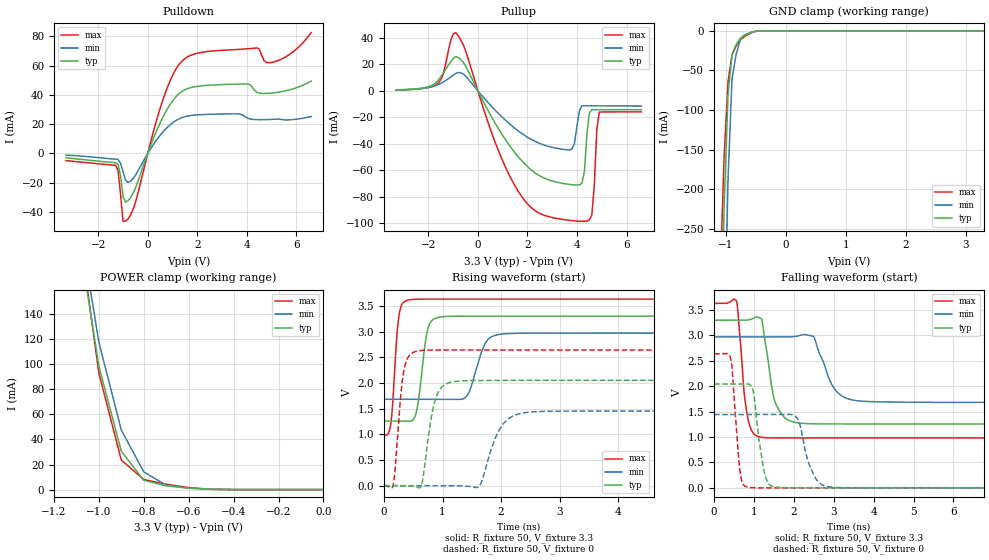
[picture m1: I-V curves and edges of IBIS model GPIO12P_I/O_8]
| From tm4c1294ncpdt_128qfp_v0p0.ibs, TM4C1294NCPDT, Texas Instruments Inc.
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|   Model Cell GPIO12P_I/O_8
[Model]   GPIO12P_I/O_8
Model_type   I/O
Polarity   Non-Inverting
Enable   Active-Low
Vinl =  0.8
Vinh =  2
Cref =  15.0000pF
Rref =  100.0000M
Vref =  0V
Vmeas =  1.65
C_comp   6.029616p   5.226915p   6.778838p
[Model Spec]
Vinl   0.8   0.8   0.8
Vinh   2   2   2
[Temperature Range]   25   125   -40
[Voltage Range]   3.3   2.97   3.63
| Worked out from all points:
|   slope of the pulldown table from 0 to 0.495 V, typ, clamps not added: 23.8 ohm
|   slope of the pullup table from 0 to 0.495 V, typ, clamps not added: 27.8 ohm
|   GND clamp passes 1 mA (typ) near -0.53 V on its own axis
|   POWER clamp passes 1 mA (typ) near -0.58 V on its own axis
|   rising waveform, R_fixture 50, V_fixture 3.3: 20-80 % time 130ps typ, 213ps min, 90.2ps max; typ from 1.26 V to 3.3 V
|   rising waveform, R_fixture 50, V_fixture 0: 20-80 % time 170ps typ, 286ps min, 117ps max; typ from 0 V to 2.04 V
|   falling waveform, R_fixture 50, V_fixture 3.3: 20-80 % time 264ps typ, 420ps min, 181ps max; typ from 3.3 V to 1.26 V
|   falling waveform, R_fixture 50, V_fixture 0: 20-80 % time 203ps typ, 301ps min, 148ps max; typ from 2.04 V to 0 V
| Nom Voltages:
|   IBIASFET=3.3, VDDC=1.2, VDD=3.3, GND=0
| Min Voltages:
|   IBIASFET=2.97, VDDC=1.08, VDD=2.97, GND=0
| Max Voltages:
|   IBIASFET=3.63, VDDC=1.32, VDD=3.63, GND=0
[POWER_clamp]
|   voltage   I(typ)   I(min)   I(max)
-3.3V     3.668A     4.187A     4.057A
-1.067V   175.6mA    191.7mA    181.3mA
-1.033V   137.2mA    154.7mA    137.2mA
-1V       98.66mA    117.8mA    93.17mA
-900mV    30.66mA    47.6mA     23.68mA
-800mV    7.454mA    14.17mA    8.045mA
-700mV    3.021mA    3.466mA    4.326mA
-600mV    1.166mA    1.15mA     1.613mA
-500mV    219.7uA    295.1uA    245.5uA
0V        69.07pA    1.982nA    9.028pA
[Pulldown]
|   voltage   I(typ)   I(min)   I(max)
-3.3V     -3.019mA   -1.206mA   -4.938mA
-1.3V     -6.416mA   -4.007mA   -8.087mA
-1.2V     -7.65mA    -4.163mA   -11.69mA
-1V       -29.59mA   -12.56mA   -46.46mA
-900mV    -33.29mA   -18.21mA   -46.32mA
-500mV    -23.81mA   -14.98mA   -33.54mA
700mV     27.72mA    16.29mA    41.06mA
1.4V      42.61mA    24.62mA    63.44mA
4V        47.51mA    24.37mA    71.53mA
4.4V      41.79mA    23.1mA     72.14mA
5V        41.27mA    23.24mA    62.2mA
6.6V      49.45mA    25.19mA    82.65mA
[Pullup]
|   voltage   I(typ)   I(min)   I(max)
-3.3V     716.3uA    635uA      605.7uA
-1.6V     8.021mA    4.755mA    5.925mA
-900mV    25.8mA     13.18mA    44.03mA
1.7V      -51.4mA    -31.27mA   -78.06mA
3.7V      -70.75mA   -44.67mA   -97.88mA
4V        -71.18mA   -26.4mA    -98.48mA
4.3V      -61.06mA   -11.3mA    -98.51mA
4.5V      -16.84mA   -11.31mA   -97.48mA
4.6V      -14.26mA   -11.32mA   -93.92mA
4.8V      -14.25mA   -11.33mA   -29.37mA
4.9V      -14.25mA   -11.34mA   -16.02mA
6.6V      -14.3mA    -11.49mA   -15.93mA
[GND_clamp]
|   voltage   I(typ)   I(min)   I(max)
-3.3V     -18.01A    -17.27A    -18.6A
-1.1V     -459.9mA   -734.3mA   -318.7mA
-1.033V   -223.6mA   -411.6mA   -160.4mA
-966.7mV  -80.12mA   -186.8mA   -64.21mA
-900mV    -29.51mA   -59.8mA    -30.11mA
-833.3mV  -17.66mA   -30.4mA    -19.41mA
-766.7mV  -9.785mA   -12.28mA   -11.96mA
-700mV    -5.884mA   -5.445mA   -7.749mA
-500mV    -484.3uA   -573uA     -552.3uA
-366.7mV  -23.48uA   -48.41uA   -21.82uA
3.3V      69.07pA    6.412uA    7.794pA
[Ramp]
| variable   typ   min   max
dV/dt_f  1.2650696/0.26678168n 0.80180967/0.4261666n  1.6395763/0.18482632n
dV/dt_r  1.2553671/0.17228477n 0.89374271/0.29145616n  1.6086857/0.11867281n
R_load = 50
[Rising Waveform]
R_fixture = 50
V_fixture = 3.3
V_fixture_min = 2.97
V_fixture_max = 3.63
|   time   V(typ)   V(min)   V(max)
0s        1.258V     1.681V     982.6mV
122.7ps   1.258V     1.681V     1.256V
272.8ps   1.258V     1.681V     3.411V
473.4ps   1.263V     1.681V     3.623V
750.1ps   3.054V     1.681V     3.63V
1.03ns    3.29V      1.681V     3.63V
1.394ns   3.299V     1.72V      3.63V
1.734ns   3.299V     2.776V     3.63V
2.106ns   3.3V       2.958V     3.63V
20.05ns   3.3V       2.97V      3.63V
[Rising Waveform]
R_fixture = 50
V_fixture = 0
V_fixture_min = 0
V_fixture_max = 0
|   time   V(typ)   V(min)   V(max)
0s        0V         0V         0V
168.1ps   0V         0V         71.79mV
366.4ps   0V         0V         2.37V
608.6ps   -41.78mV   0V         2.627V
886.1ps   1.708V     0V         2.639V
1.28ns    2.035V     0V         2.64V
1.627ns   2.047V     -10.95mV   2.64V
2.037ns   2.049V     1.203V     2.64V
2.591ns   2.049V     1.439V     2.64V
20.01ns   2.045V     1.447V     2.639V
[Falling Waveform]
R_fixture = 50
V_fixture = 3.3
V_fixture_min = 2.97
V_fixture_max = 3.63
|   time   V(typ)   V(min)   V(max)
0s        3.3V       2.97V      3.63V
562.4ps   3.3V       2.97V      3.678V
845.2ps   3.304V     2.97V      1.378V
1.221ns   3.208V     2.97V      991.3mV
1.535ns   1.677V     2.97V      982.4mV
2.078ns   1.281V     2.986V     982.7mV
2.493ns   1.261V     2.979V     982.8mV
3.014ns   1.258V     1.955V     982.8mV
3.595ns   1.258V     1.714V     982.8mV
20.05ns   1.258V     1.681V     982.8mV
[Falling Waveform]
R_fixture = 50
V_fixture = 0
V_fixture_min = 0
V_fixture_max = 0
|   time   V(typ)   V(min)   V(max)
0s        2.045V     1.443V     2.639V
419.3ps   2.045V     1.443V     2.537V
658.4ps   2.045V     1.443V     283.8mV
873.1ps   2.041V     1.443V     10.98mV
1.269ns   275.4mV    1.443V     0V
1.556ns   13.48mV    1.443V     0V
2.09ns    0V         1.363V     0V
2.509ns   0V         239.9mV    0V
2.95ns    0V         13.31mV    0V
20.01ns   0V         0V         0V
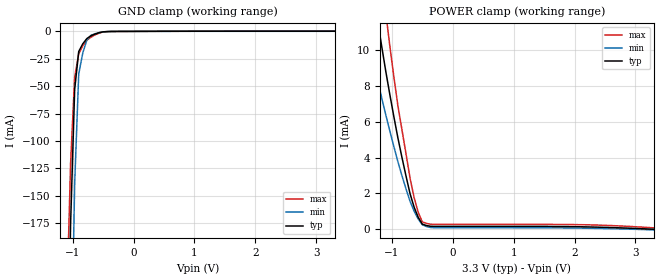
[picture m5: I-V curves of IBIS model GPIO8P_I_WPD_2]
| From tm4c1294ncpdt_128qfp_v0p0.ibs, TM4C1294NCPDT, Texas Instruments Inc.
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|   Model Cell GPIO8P_I_WPD_2
[Model]   GPIO8P_I_WPD_2
Model_type   Input
Polarity   Non-Inverting
Vinl =  0.8
Vinh =  2
C_comp   5.378567p   4.597605p   6.118031p
[Model Spec]
Vinl   0.8   0.8   0.8
Vinh   2   2   2
[Temperature Range]   25   125   -40
[Voltage Range]   3.3   2.97   3.63
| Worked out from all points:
|   GND clamp passes 1 mA (typ) near -0.55 V on its own axis
|   POWER clamp passes 1 mA (typ) near -0.61 V on its own axis
| Nom Voltages:
|   VBAT=3.3, VDDC=1.2, VDD=3.3, GND=0
| Min Voltages:
|   VBAT=2.97, VDDC=1.08, VDD=2.97, GND=0
| Max Voltages:
|   VBAT=3.63, VDDC=1.32, VDD=3.63, GND=0
[POWER_clamp]
|   voltage   I(typ)   I(min)   I(max)
-3.3V     116.2mA    496.9mA    244.4mA
-1.433V   16.2mA     11.38mA    22.74mA
-1.367V   14.64mA    10.33mA    20.49mA
-1.233V   11.65mA    8.31mA     16.16mA
-1.167V   10.22mA    7.341mA    14.1mA
-1.1V     8.833mA    6.394mA    12.1mA
-1.033V   7.534mA    5.493mA    10.25mA
-900mV    5.094mA    3.77mA     6.887mA
-700mV    1.977mA    1.554mA    2.841mA
-566.7mV  664.4uA    572.2uA    945.9uA
-500mV    286.6uA    251.9uA    414.4uA
3.3V      -84.1pA    -40.96uA   78.8uA
[GND_clamp]
|   voltage   I(typ)   I(min)   I(max)
-3.3V     -16.39A    -15.37A    -17.22A
-1.1V     -384.9mA   -635.5mA   -255.1mA
-1.033V   -175.3mA   -338.1mA   -120.1mA
-966.7mV  -53.1mA    -139.3mA   -41.81mA
-900mV    -18.34mA   -38.91mA   -20.35mA
-833.3mV  -11.35mA   -19.63mA   -13.16mA
-766.7mV  -6.571mA   -7.874mA   -8.146mA
-700mV    -4.009mA   -3.63mA    -5.304mA
-500mV    -404.6uA   -428.5uA   -493.4uA
-366.7mV  -78.46uA   -69.36uA   -110.5uA
3.3V      162.1uA    87.19uA    277.3uA
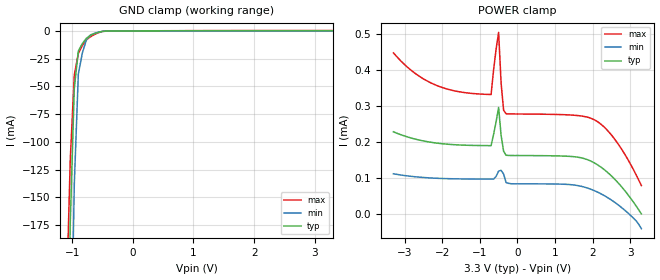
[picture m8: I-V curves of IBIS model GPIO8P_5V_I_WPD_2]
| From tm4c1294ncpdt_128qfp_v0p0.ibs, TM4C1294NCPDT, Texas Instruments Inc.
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|   Model Cell GPIO8P_5V_I_WPD_2
[Model]   GPIO8P_5V_I_WPD_2
Model_type   Input
Polarity   Non-Inverting
Vinl =  0.8
Vinh =  2
C_comp   7.738177p   6.063161p   9.392973p
[Model Spec]
Vinl   0.8   0.8   0.8
Vinh   2   2   2
[Temperature Range]   25   125   -40
[Voltage Range]   3.3   2.97   3.63
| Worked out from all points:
|   GND clamp passes 1 mA (typ) near -0.55 V on its own axis
| Nom Voltages:
|   VDDC=1.2, VDD=3.3, GND=0
| Min Voltages:
|   VDDC=1.08, VDD=2.97, GND=0
| Max Voltages:
|   VDDC=1.32, VDD=3.63, GND=0
[POWER_clamp]
|   voltage   I(typ)   I(min)   I(max)
-3.3V     228.1uA    111.4uA    447.3uA
-2.767V   209.1uA    103.7uA    393.9uA
-2.167V   197uA      99.07uA    357.6uA
-700mV    189.6uA    96.73uA    331.6uA
-500mV    295.6uA    118.9uA    504.2uA
-433.3mV  218.1uA    121.1uA    363.2uA
-366.7mV  173.9uA    110.4uA    287.8uA
-300mV    162.9uA    86.89uA    278.1uA
1.5V      158.9uA    80.38uA    274.2uA
2.1V      138.6uA    62.26uA    258.5uA
2.7V      84.22uA    23.72uA    191.6uA
3.3V      -134.1pA   -40.99uA   78.8uA
[GND_clamp]
|   voltage   I(typ)   I(min)   I(max)
-3.3V     -16.36A    -15.34A    -17.18A
-1.1V     -382.1mA   -633.4mA   -250.1mA
-1.033V   -173.3mA   -336.5mA   -116.4mA
-966.7mV  -52.02mA   -138.4mA   -39.8mA
-900mV    -18.2mA    -38.98mA   -20.33mA
-833.3mV  -11.36mA   -19.82mA   -13.17mA
-766.7mV  -6.626mA   -8.055mA   -8.158mA
-700mV    -4.013mA   -3.686mA   -5.306mA
-500mV    -405.1uA   -429.6uA   -494.1uA
-366.7mV  -78.5uA    -69.47uA   -110.5uA
3.3V      162.1uA    90.74uA    277.3uA
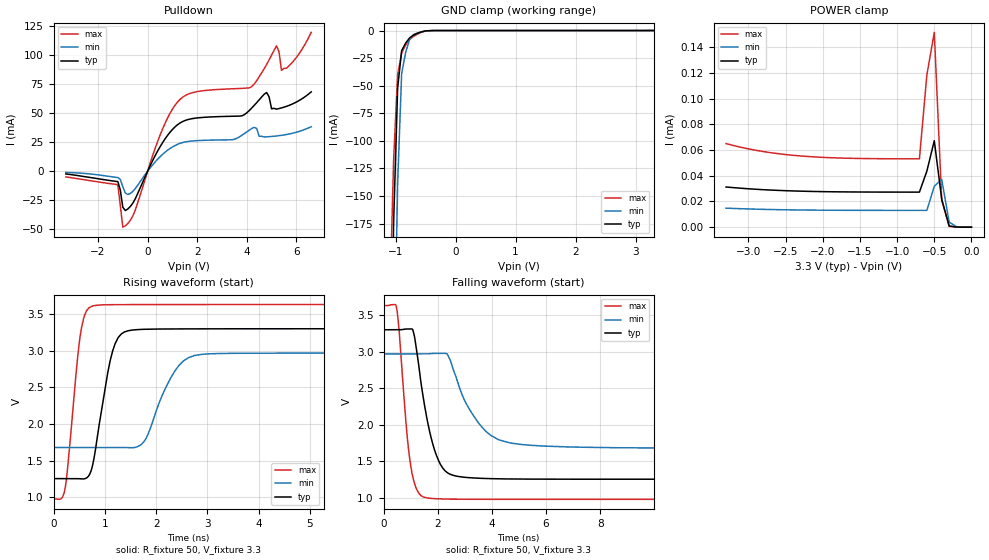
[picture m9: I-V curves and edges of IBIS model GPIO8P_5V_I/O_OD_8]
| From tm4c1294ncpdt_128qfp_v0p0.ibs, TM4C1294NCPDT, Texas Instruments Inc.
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|   Model Cell GPIO8P_5V_I/O_OD_8
[Model]   GPIO8P_5V_I/O_OD_8
Model_type   I/O_open_drain
Polarity   Inverting
Enable   Active-Low
Vinl =  0.8
Vinh =  2
Cref =  15.0000pF
Rref =  100.0000M
Vref =  0V
Vmeas =  1.65
C_comp   7.738177p   6.063161p   9.392973p
[Model Spec]
Vinl   0.8   0.8   0.8
Vinh   2   2   2
[Temperature Range]   25   125   -40
[Voltage Range]   3.3   2.97   3.63
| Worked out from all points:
|   slope of the pulldown table from 0 to 0.495 V, typ, clamps not added: 23.8 ohm
|   GND clamp passes 1 mA (typ) near -0.55 V on its own axis
|   rising waveform, R_fixture 50, V_fixture 3.3: 20-80 % time 294ps typ, 469ps min, 211ps max; typ from 1.26 V to 3.3 V
|   falling waveform, R_fixture 50, V_fixture 3.3: 20-80 % time 603ps typ, 1.09ns min, 361ps max; typ from 3.3 V to 1.26 V
| Nom Voltages:
|   VDDC=1.2, VDD=3.3, GND=0
| Min Voltages:
|   VDDC=1.08, VDD=2.97, GND=0
| Max Voltages:
|   VDDC=1.32, VDD=3.63, GND=0
[POWER_clamp]
|   voltage   I(typ)   I(min)   I(max)
-3.3V     31.22uA    14.77uA    64.95uA
-2.8V     29.13uA    13.84uA    58.77uA
-2.3V     27.98uA    13.34uA    55.36uA
-1.7V     27.4uA     13.1uA     53.62uA
-700mV    27.24uA    13.03uA    53.12uA
-600mV    43.52uA    13.03uA    118.2uA
-500mV    67.2uA     31.8uA     151.5uA
-400mV    21.58uA    37.04uA    21.1uA
-300mV    927.4nA    3.873uA    611.4nA
-200mV    28.93nA    266.5nA    11.51nA
0V        696.9pA    10.99nA    568.3pA
[Pulldown]
|   voltage   I(typ)   I(min)   I(max)
-3.3V     -2.325mA   -1.011mA   -4.829mA
-1.2V     -8.9mA     -5.443mA   -11.78mA
-1V       -30.94mA   -13.35mA   -48.07mA
-900mV    -33.77mA   -18.67mA   -46.9mA
-500mV    -23.82mA   -14.99mA   -33.55mA
600mV     24.46mA    14.43mA    36.18mA
1.3V      41.39mA    23.95mA    61.62mA
4.2V      54.39mA    36.75mA    72.77mA
4.8V      67.66mA    29.61mA    91.8mA
5.2V      53.41mA    30.34mA    107.8mA
5.4V      54.46mA    30.89mA    86.79mA
6.6V      68.25mA    38.26mA    119.5mA
[GND_clamp]
|   voltage   I(typ)   I(min)   I(max)
-3.3V     -16.36A    -15.34A    -17.18A
-1.1V     -382.1mA   -633.4mA   -250.1mA
-1.033V   -173.3mA   -336.5mA   -116.4mA
-966.7mV  -52.02mA   -138.4mA   -39.81mA
-900mV    -18.21mA   -38.98mA   -20.34mA
-833.3mV  -11.36mA   -19.82mA   -13.17mA
-766.7mV  -6.618mA   -8.051mA   -8.134mA
-700mV    -3.983mA   -3.675mA   -5.247mA
-500mV    -328.3uA   -388.2uA   -374.5uA
-366.7mV  -15.94uA   -32.84uA   -14.83uA
3.3V      696.9pA    8.348uA    426.1pA
[Ramp]
| variable   typ   min   max
dV/dt_f  1.2327476/0.60421965n 0.77839191/1.0956499n  1.5975129/0.36234264n
dV/dt_r  1.2367608/0.5327977n 0.87779632/1.1244503n  1.5908858/0.32349379n
R_load = 50
[Rising Waveform]
R_fixture = 50
V_fixture = 3.3
V_fixture_min = 2.97
V_fixture_max = 3.63
|   time   V(typ)   V(min)   V(max)
0s        1.258V     1.681V     982.1mV
222.4ps   1.258V     1.681V     1.113V
517.4ps   1.255V     1.681V     3.191V
787.1ps   1.526V     1.681V     3.613V
1.153ns   2.997V     1.681V     3.628V
1.534ns   3.282V     1.678V     3.629V
1.804ns   3.293V     1.805V     3.629V
2.441ns   3.297V     2.796V     3.63V
2.892ns   3.298V     2.951V     3.63V
20.01ns   3.3V       2.97V      3.63V
[Falling Waveform]
R_fixture = 50
V_fixture = 3.3
V_fixture_min = 2.97
V_fixture_max = 3.63
|   time   V(typ)   V(min)   V(max)
0s        3.3V       2.97V      3.63V
465ps     3.3V       2.97V      3.62V
975.4ps   3.312V     2.97V      1.5V
1.145ns   3.196V     2.97V      1.195V
1.465ns   2.368V     2.97V      1.015V
2.009ns   1.528V     2.978V     989.8mV
2.738ns   1.296V     2.582V     984.5mV
3.621ns   1.269V     1.973V     983mV
4.67ns    1.261V     1.754V     982.8mV
20.01ns   1.258V     1.681V     982.8mV
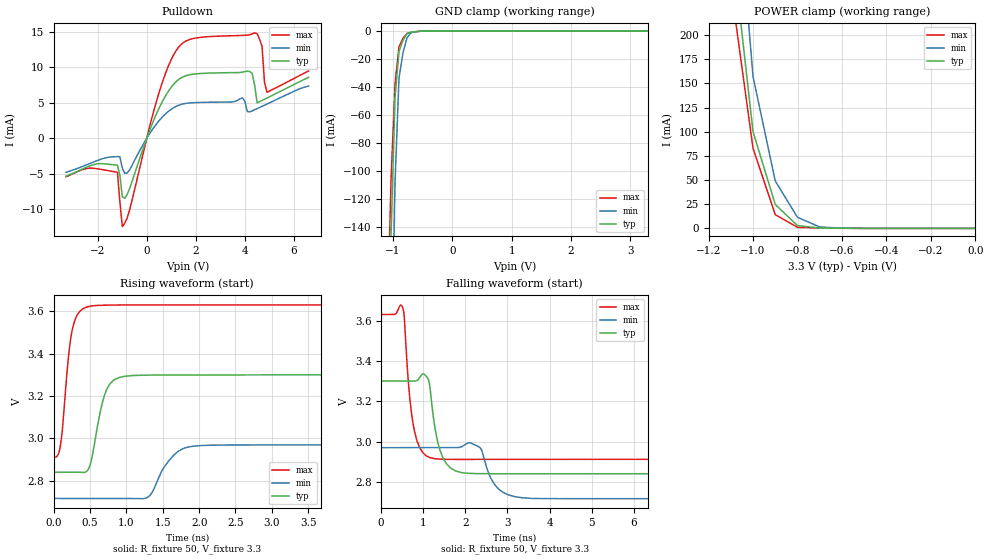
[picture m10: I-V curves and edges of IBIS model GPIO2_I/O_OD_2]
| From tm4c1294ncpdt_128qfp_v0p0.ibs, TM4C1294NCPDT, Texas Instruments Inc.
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|   Model Cell GPIO2_I/O_OD_2
[Model]   GPIO2_I/O_OD_2
Model_type   I/O_open_drain
Polarity   Inverting
Enable   Active-Low
Vinl =  0.8
Vinh =  2
Cref =  15.0000pF
Rref =  100.0000M
Vref =  0V
Vmeas =  1.65
C_comp   3.906872p   3.211855p   4.659324p
[Model Spec]
Vinl   0.8   0.8   0.8
Vinh   2   2   2
[Temperature Range]   25   125   -40
[Voltage Range]   3.3   2.97   3.63
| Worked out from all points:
|   slope of the pulldown table from 0 to 0.495 V, typ, clamps not added: 118 ohm
|   GND clamp passes 1 mA (typ) near -0.71 V on its own axis
|   POWER clamp passes 1 mA (typ) near -0.73 V on its own axis
|   rising waveform, R_fixture 50, V_fixture 3.3: 20-80 % time 165ps typ, 260ps min, 118ps max; typ from 2.84 V to 3.3 V
|   falling waveform, R_fixture 50, V_fixture 3.3: 20-80 % time 251ps typ, 338ps min, 202ps max; typ from 3.3 V to 2.84 V
| Nom Voltages:
|   IBIASFET=3.3, VDDC=1.2, VDDA=3.3, VDD=3.3, GND=0, GNDA=0
| Min Voltages:
|   IBIASFET=2.97, VDDC=1.08, VDDA=2.97, VDD=2.97, GND=0, GNDA=0
| Max Voltages:
|   IBIASFET=3.63, VDDC=1.32, VDDA=3.63, VDD=3.63, GND=0, GNDA=0
[POWER_clamp]
|   voltage   I(typ)   I(min)   I(max)
-3.3V     12.79A     11.7A      13.85A
-1.1V     304.7mA    435.8mA    251.1mA
-1.067V   236.5mA    342.9mA    195mA
-1.033V   168.3mA    250mA      138.9mA
-1V       100.1mA    157mA      82.84mA
-900mV    24.74mA    49.05mA    14.21mA
-800mV    2.84mA     11.39mA    1.081mA
-700mV    384.7uA    1.467mA    398.7uA
-600mV    110.1uA    213.8uA    128.7uA
0V        4.099pA    321.3pA    -3.579pA
[Pulldown]
|   voltage   I(typ)   I(min)   I(max)
-3.3V     -5.378mA   -4.816mA   -5.461mA
-1.2V     -3.806mA   -2.612mA   -4.816mA
-1V       -8.265mA   -4.244mA   -12.47mA
700mV     5.566mA    3.205mA    8.526mA
1.7V      8.888mA    4.934mA    13.83mA
3.9V      9.287mA    5.668mA    14.47mA
4.2V      9.362mA    3.692mA    14.56mA
4.5V      4.968mA    4.151mA    14.7mA
4.7V      5.294mA    4.472mA    12.92mA
4.8V      5.463mA    4.635mA    7.89mA
4.9V      5.635mA    4.798mA    6.454mA
6.6V      8.559mA    7.346mA    9.467mA
[GND_clamp]
|   voltage   I(typ)   I(min)   I(max)
-3.3V     -13.29A    -11.97A    -14.49A
-1.1V     -307.5mA   -503mA     -215mA
-1.033V   -145.1mA   -264.7mA   -105.5mA
-966.7mV  -47.5mA    -108.3mA   -37.63mA
-900mV    -14.58mA   -33.66mA   -11.32mA
-833.3mV  -6.592mA   -15.8mA    -5.233mA
-766.7mV  -2.012mA   -5.009mA   -1.803mA
-700mV    -844.5uA   -1.291mA   -1.03mA
-500mV    -48.1uA    -74.86uA   -41.06uA
3.3V      4.086pA    607nA      -4.095pA
[Ramp]
| variable   typ   min   max
dV/dt_f 0.29723109/0.25164659n 0.16674833/0.33932608n 0.45950538/0.20377875n
dV/dt_r 0.20971817/0.3634721n 0.12319155/0.57097451n 0.31986018/0.26335086n
R_load = 50
[Rising Waveform]
R_fixture = 50
V_fixture = 3.3
V_fixture_min = 2.97
V_fixture_max = 3.63
|   time   V(typ)   V(min)   V(max)
0s        2.841V     2.717V     2.912V
93.3ps    2.841V     2.717V     2.972V
199.6ps   2.841V     2.717V     3.38V
270.5ps   2.841V     2.717V     3.537V
523.4ps   2.908V     2.717V     3.626V
737.3ps   3.238V     2.717V     3.629V
1.067ns   3.297V     2.717V     3.63V
1.723ns   3.3V       2.942V     3.63V
2.051ns   3.3V       2.967V     3.63V
20.04ns   3.3V       2.97V      3.63V
[Falling Waveform]
R_fixture = 50
V_fixture = 3.3
V_fixture_min = 2.97
V_fixture_max = 3.63
|   time   V(typ)   V(min)   V(max)
0s        3.3V       2.97V      3.63V
503.5ps   3.3V       2.97V      3.668V
792.3ps   3.3V       2.97V      3.051V
1.129ns   3.304V     2.97V      2.924V
1.287ns   3.057V     2.97V      2.915V
1.759ns   2.855V     2.97V      2.912V
2.341ns   2.841V     2.971V     2.912V
2.709ns   2.841V     2.784V     2.912V
3.361ns   2.841V     2.721V     2.912V
20.04ns   2.841V     2.717V     2.912V
